VERSION 5.7 ;
  NOWIREEXTENSIONATPIN ON ;
  DIVIDERCHAR "/" ;
  BUSBITCHARS "[]" ;
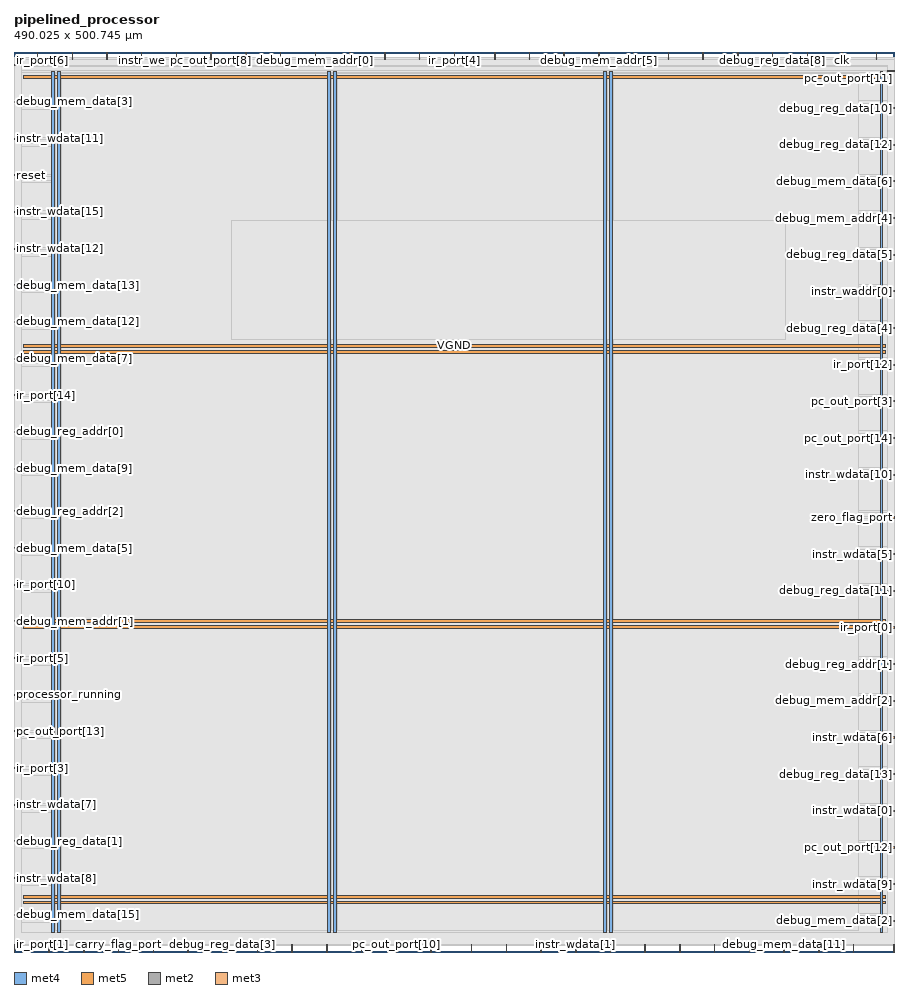
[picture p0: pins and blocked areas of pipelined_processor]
MACRO pipelined_processor
  CLASS BLOCK ;
  FOREIGN pipelined_processor ;
  ORIGIN 0.000 0.000 ;
  SIZE 490.025 BY 500.745 ;
  PIN VGND
    DIRECTION INOUT ;
    USE GROUND ;
    PORT
      LAYER met4 ;
        RECT 24.340 10.640 25.940 489.840 ;
    END
    PORT
      LAYER met4 ;
        RECT 177.940 10.640 179.540 489.840 ;
    END
    PORT
      LAYER met4 ;
        RECT 331.540 10.640 333.140 489.840 ;
    END
    PORT
      LAYER met5 ;
        RECT 5.280 30.030 484.620 31.630 ;
    END
    PORT
      LAYER met5 ;
        RECT 5.280 183.210 484.620 184.810 ;
    END
    PORT
      LAYER met5 ;
        RECT 5.280 336.390 484.620 337.990 ;
    END
  END VGND
  PIN VPWR
    DIRECTION INOUT ;
    USE POWER ;
    PORT
      LAYER met4 ;
        RECT 21.040 10.640 22.640 489.840 ;
    END
    PORT
      LAYER met4 ;
        RECT 174.640 10.640 176.240 489.840 ;
    END
    PORT
      LAYER met4 ;
        RECT 328.240 10.640 329.840 489.840 ;
    END
    PORT
      LAYER met4 ;
        RECT 481.840 10.640 483.440 489.840 ;
    END
    PORT
      LAYER met5 ;
        RECT 5.280 26.730 484.620 28.330 ;
    END
    PORT
      LAYER met5 ;
        RECT 5.280 179.910 484.620 181.510 ;
    END
    PORT
      LAYER met5 ;
        RECT 5.280 333.090 484.620 334.690 ;
    END
    PORT
      LAYER met5 ;
        RECT 5.280 486.270 484.620 487.870 ;
    END
  END VPWR
  PIN carry_flag_port
    DIRECTION OUTPUT TRISTATE ;
    USE SIGNAL ;
    ANTENNADIFFAREA 0.795200 ;
    PORT
      LAYER met2 ;
        RECT 58.050 0.000 58.330 4.000 ;
    END
  END carry_flag_port
  PIN clk
    DIRECTION INPUT ;
    USE SIGNAL ;
    ANTENNAGATEAREA 1.286700 ;
    ANTENNADIFFAREA 0.434700 ;
    PORT
      LAYER met2 ;
        RECT 460.550 496.745 460.830 500.745 ;
    END
  END clk
  PIN debug_mem_addr[0]
    DIRECTION INPUT ;
    USE SIGNAL ;
    ANTENNAGATEAREA 0.213000 ;
    PORT
      LAYER met2 ;
        RECT 167.530 496.745 167.810 500.745 ;
    END
  END debug_mem_addr[0]
  PIN debug_mem_addr[1]
    DIRECTION INPUT ;
    USE SIGNAL ;
    ANTENNAGATEAREA 0.247500 ;
    PORT
      LAYER met3 ;
        RECT 0.000 183.640 4.000 184.240 ;
    END
  END debug_mem_addr[1]
  PIN debug_mem_addr[2]
    DIRECTION INPUT ;
    USE SIGNAL ;
    ANTENNAGATEAREA 0.159000 ;
    PORT
      LAYER met3 ;
        RECT 486.025 139.440 490.025 140.040 ;
    END
  END debug_mem_addr[2]
  PIN debug_mem_addr[3]
    DIRECTION INPUT ;
    USE SIGNAL ;
    ANTENNAGATEAREA 0.213000 ;
    PORT
      LAYER met2 ;
        RECT 363.950 496.745 364.230 500.745 ;
    END
  END debug_mem_addr[3]
  PIN debug_mem_addr[4]
    DIRECTION INPUT ;
    USE SIGNAL ;
    ANTENNAGATEAREA 0.247500 ;
    PORT
      LAYER met3 ;
        RECT 486.025 408.040 490.025 408.640 ;
    END
  END debug_mem_addr[4]
  PIN debug_mem_addr[5]
    DIRECTION INPUT ;
    USE SIGNAL ;
    ANTENNAGATEAREA 0.159000 ;
    PORT
      LAYER met2 ;
        RECT 325.310 496.745 325.590 500.745 ;
    END
  END debug_mem_addr[5]
  PIN debug_mem_data[0]
    DIRECTION OUTPUT TRISTATE ;
    USE SIGNAL ;
    ANTENNADIFFAREA 0.795200 ;
    PORT
      LAYER met2 ;
        RECT 409.030 0.000 409.310 4.000 ;
    END
  END debug_mem_data[0]
  PIN debug_mem_data[10]
    DIRECTION OUTPUT TRISTATE ;
    USE SIGNAL ;
    ANTENNADIFFAREA 0.795200 ;
    PORT
      LAYER met2 ;
        RECT 186.850 496.745 187.130 500.745 ;
    END
  END debug_mem_data[10]
  PIN debug_mem_data[11]
    DIRECTION OUTPUT TRISTATE ;
    USE SIGNAL ;
    ANTENNADIFFAREA 0.795200 ;
    PORT
      LAYER met2 ;
        RECT 428.350 0.000 428.630 4.000 ;
    END
  END debug_mem_data[11]
  PIN debug_mem_data[12]
    DIRECTION OUTPUT TRISTATE ;
    USE SIGNAL ;
    ANTENNADIFFAREA 0.795200 ;
    PORT
      LAYER met3 ;
        RECT 0.000 350.240 4.000 350.840 ;
    END
  END debug_mem_data[12]
  PIN debug_mem_data[13]
    DIRECTION OUTPUT TRISTATE ;
    USE SIGNAL ;
    ANTENNADIFFAREA 0.795200 ;
    PORT
      LAYER met3 ;
        RECT 0.000 370.640 4.000 371.240 ;
    END
  END debug_mem_data[13]
  PIN debug_mem_data[14]
    DIRECTION OUTPUT TRISTATE ;
    USE SIGNAL ;
    ANTENNADIFFAREA 0.795200 ;
    PORT
      LAYER met2 ;
        RECT 351.070 0.000 351.350 4.000 ;
    END
  END debug_mem_data[14]
  PIN debug_mem_data[15]
    DIRECTION OUTPUT TRISTATE ;
    USE SIGNAL ;
    ANTENNADIFFAREA 0.795200 ;
    PORT
      LAYER met3 ;
        RECT 0.000 20.440 4.000 21.040 ;
    END
  END debug_mem_data[15]
  PIN debug_mem_data[1]
    DIRECTION OUTPUT TRISTATE ;
    USE SIGNAL ;
    ANTENNADIFFAREA 0.795200 ;
    PORT
      LAYER met2 ;
        RECT 148.210 496.745 148.490 500.745 ;
    END
  END debug_mem_data[1]
  PIN debug_mem_data[2]
    DIRECTION OUTPUT TRISTATE ;
    USE SIGNAL ;
    ANTENNADIFFAREA 0.445500 ;
    PORT
      LAYER met3 ;
        RECT 486.025 17.040 490.025 17.640 ;
    END
  END debug_mem_data[2]
  PIN debug_mem_data[3]
    DIRECTION OUTPUT TRISTATE ;
    USE SIGNAL ;
    ANTENNADIFFAREA 0.795200 ;
    PORT
      LAYER met3 ;
        RECT 0.000 472.640 4.000 473.240 ;
    END
  END debug_mem_data[3]
  PIN debug_mem_data[4]
    DIRECTION OUTPUT TRISTATE ;
    USE SIGNAL ;
    ANTENNADIFFAREA 0.795200 ;
    PORT
      LAYER met2 ;
        RECT 466.990 0.000 467.270 4.000 ;
    END
  END debug_mem_data[4]
  PIN debug_mem_data[5]
    DIRECTION OUTPUT TRISTATE ;
    USE SIGNAL ;
    ANTENNADIFFAREA 0.795200 ;
    PORT
      LAYER met3 ;
        RECT 0.000 224.440 4.000 225.040 ;
    END
  END debug_mem_data[5]
  PIN debug_mem_data[6]
    DIRECTION OUTPUT TRISTATE ;
    USE SIGNAL ;
    ANTENNADIFFAREA 0.795200 ;
    PORT
      LAYER met3 ;
        RECT 486.025 428.440 490.025 429.040 ;
    END
  END debug_mem_data[6]
  PIN debug_mem_data[7]
    DIRECTION OUTPUT TRISTATE ;
    USE SIGNAL ;
    ANTENNADIFFAREA 0.795200 ;
    PORT
      LAYER met3 ;
        RECT 0.000 329.840 4.000 330.440 ;
    END
  END debug_mem_data[7]
  PIN debug_mem_data[8]
    DIRECTION OUTPUT TRISTATE ;
    USE SIGNAL ;
    ANTENNADIFFAREA 0.795200 ;
    PORT
      LAYER met2 ;
        RECT 51.610 496.745 51.890 500.745 ;
    END
  END debug_mem_data[8]
  PIN debug_mem_data[9]
    DIRECTION OUTPUT TRISTATE ;
    USE SIGNAL ;
    ANTENNADIFFAREA 0.795200 ;
    PORT
      LAYER met3 ;
        RECT 0.000 268.640 4.000 269.240 ;
    END
  END debug_mem_data[9]
  PIN debug_reg_addr[0]
    DIRECTION INPUT ;
    USE SIGNAL ;
    ANTENNAGATEAREA 0.247500 ;
    PORT
      LAYER met3 ;
        RECT 0.000 289.040 4.000 289.640 ;
    END
  END debug_reg_addr[0]
  PIN debug_reg_addr[1]
    DIRECTION INPUT ;
    USE SIGNAL ;
    ANTENNAGATEAREA 0.213000 ;
    PORT
      LAYER met3 ;
        RECT 486.025 159.840 490.025 160.440 ;
    END
  END debug_reg_addr[1]
  PIN debug_reg_addr[2]
    DIRECTION INPUT ;
    USE SIGNAL ;
    ANTENNAGATEAREA 0.247500 ;
    PORT
      LAYER met3 ;
        RECT 0.000 244.840 4.000 245.440 ;
    END
  END debug_reg_addr[2]
  PIN debug_reg_data[0]
    DIRECTION OUTPUT TRISTATE ;
    USE SIGNAL ;
    ANTENNADIFFAREA 0.795200 ;
    PORT
      LAYER met2 ;
        RECT 193.290 0.000 193.570 4.000 ;
    END
  END debug_reg_data[0]
  PIN debug_reg_data[10]
    DIRECTION OUTPUT TRISTATE ;
    USE SIGNAL ;
    ANTENNADIFFAREA 0.795200 ;
    PORT
      LAYER met3 ;
        RECT 486.025 469.240 490.025 469.840 ;
    END
  END debug_reg_data[10]
  PIN debug_reg_data[11]
    DIRECTION OUTPUT TRISTATE ;
    USE SIGNAL ;
    ANTENNADIFFAREA 0.795200 ;
    PORT
      LAYER met3 ;
        RECT 486.025 200.640 490.025 201.240 ;
    END
  END debug_reg_data[11]
  PIN debug_reg_data[12]
    DIRECTION OUTPUT TRISTATE ;
    USE SIGNAL ;
    ANTENNADIFFAREA 0.795200 ;
    PORT
      LAYER met3 ;
        RECT 486.025 448.840 490.025 449.440 ;
    END
  END debug_reg_data[12]
  PIN debug_reg_data[13]
    DIRECTION OUTPUT TRISTATE ;
    USE SIGNAL ;
    ANTENNADIFFAREA 0.795200 ;
    PORT
      LAYER met3 ;
        RECT 486.025 98.640 490.025 99.240 ;
    END
  END debug_reg_data[13]
  PIN debug_reg_data[14]
    DIRECTION OUTPUT TRISTATE ;
    USE SIGNAL ;
    ANTENNADIFFAREA 0.795200 ;
    PORT
      LAYER met2 ;
        RECT 305.990 496.745 306.270 500.745 ;
    END
  END debug_reg_data[14]
  PIN debug_reg_data[15]
    DIRECTION OUTPUT TRISTATE ;
    USE SIGNAL ;
    ANTENNADIFFAREA 0.795200 ;
    PORT
      LAYER met2 ;
        RECT 225.490 496.745 225.770 500.745 ;
    END
  END debug_reg_data[15]
  PIN debug_reg_data[1]
    DIRECTION OUTPUT TRISTATE ;
    USE SIGNAL ;
    ANTENNADIFFAREA 0.795200 ;
    PORT
      LAYER met3 ;
        RECT 0.000 61.240 4.000 61.840 ;
    END
  END debug_reg_data[1]
  PIN debug_reg_data[2]
    DIRECTION OUTPUT TRISTATE ;
    USE SIGNAL ;
    ANTENNADIFFAREA 0.795200 ;
    PORT
      LAYER met3 ;
        RECT 0.000 493.040 4.000 493.640 ;
    END
  END debug_reg_data[2]
  PIN debug_reg_data[3]
    DIRECTION OUTPUT TRISTATE ;
    USE SIGNAL ;
    ANTENNADIFFAREA 0.795200 ;
    PORT
      LAYER met2 ;
        RECT 116.010 0.000 116.290 4.000 ;
    END
  END debug_reg_data[3]
  PIN debug_reg_data[4]
    DIRECTION OUTPUT TRISTATE ;
    USE SIGNAL ;
    ANTENNADIFFAREA 0.445500 ;
    PORT
      LAYER met3 ;
        RECT 486.025 346.840 490.025 347.440 ;
    END
  END debug_reg_data[4]
  PIN debug_reg_data[5]
    DIRECTION OUTPUT TRISTATE ;
    USE SIGNAL ;
    ANTENNADIFFAREA 0.795200 ;
    PORT
      LAYER met3 ;
        RECT 486.025 387.640 490.025 388.240 ;
    END
  END debug_reg_data[5]
  PIN debug_reg_data[6]
    DIRECTION OUTPUT TRISTATE ;
    USE SIGNAL ;
    ANTENNADIFFAREA 0.795200 ;
    PORT
      LAYER met2 ;
        RECT 206.170 496.745 206.450 500.745 ;
    END
  END debug_reg_data[6]
  PIN debug_reg_data[7]
    DIRECTION OUTPUT TRISTATE ;
    USE SIGNAL ;
    ANTENNADIFFAREA 0.795200 ;
    PORT
      LAYER met2 ;
        RECT 267.350 496.745 267.630 500.745 ;
    END
  END debug_reg_data[7]
  PIN debug_reg_data[8]
    DIRECTION OUTPUT TRISTATE ;
    USE SIGNAL ;
    ANTENNADIFFAREA 0.795200 ;
    PORT
      LAYER met2 ;
        RECT 421.910 496.745 422.190 500.745 ;
    END
  END debug_reg_data[8]
  PIN debug_reg_data[9]
    DIRECTION OUTPUT TRISTATE ;
    USE SIGNAL ;
    ANTENNADIFFAREA 0.795200 ;
    PORT
      LAYER met2 ;
        RECT 489.530 0.000 489.810 4.000 ;
    END
  END debug_reg_data[9]
  PIN instr_waddr[0]
    DIRECTION INPUT ;
    USE SIGNAL ;
    ANTENNAGATEAREA 0.426000 ;
    PORT
      LAYER met3 ;
        RECT 486.025 367.240 490.025 367.840 ;
    END
  END instr_waddr[0]
  PIN instr_waddr[1]
    DIRECTION INPUT ;
    USE SIGNAL ;
    ANTENNAGATEAREA 0.426000 ;
    PORT
      LAYER met2 ;
        RECT 479.870 496.745 480.150 500.745 ;
    END
  END instr_waddr[1]
  PIN instr_waddr[2]
    DIRECTION INPUT ;
    USE SIGNAL ;
    ANTENNAGATEAREA 0.426000 ;
    PORT
      LAYER met2 ;
        RECT 286.670 496.745 286.950 500.745 ;
    END
  END instr_waddr[2]
  PIN instr_waddr[3]
    DIRECTION INPUT ;
    USE SIGNAL ;
    ANTENNAGATEAREA 0.213000 ;
    PORT
      LAYER met2 ;
        RECT 173.970 0.000 174.250 4.000 ;
    END
  END instr_waddr[3]
  PIN instr_wdata[0]
    DIRECTION INPUT ;
    USE SIGNAL ;
    ANTENNAGATEAREA 0.213000 ;
    PORT
      LAYER met3 ;
        RECT 486.025 78.240 490.025 78.840 ;
    END
  END instr_wdata[0]
  PIN instr_wdata[10]
    DIRECTION INPUT ;
    USE SIGNAL ;
    ANTENNAGATEAREA 0.213000 ;
    PORT
      LAYER met3 ;
        RECT 486.025 265.240 490.025 265.840 ;
    END
  END instr_wdata[10]
  PIN instr_wdata[11]
    DIRECTION INPUT ;
    USE SIGNAL ;
    ANTENNAGATEAREA 0.213000 ;
    PORT
      LAYER met3 ;
        RECT 0.000 452.240 4.000 452.840 ;
    END
  END instr_wdata[11]
  PIN instr_wdata[12]
    DIRECTION INPUT ;
    USE SIGNAL ;
    ANTENNAGATEAREA 0.213000 ;
    PORT
      LAYER met3 ;
        RECT 0.000 391.040 4.000 391.640 ;
    END
  END instr_wdata[12]
  PIN instr_wdata[13]
    DIRECTION INPUT ;
    USE SIGNAL ;
    ANTENNAGATEAREA 0.159000 ;
    PORT
      LAYER met2 ;
        RECT 128.890 496.745 129.170 500.745 ;
    END
  END instr_wdata[13]
  PIN instr_wdata[14]
    DIRECTION INPUT ;
    USE SIGNAL ;
    ANTENNAGATEAREA 0.213000 ;
    PORT
      LAYER met2 ;
        RECT 370.390 0.000 370.670 4.000 ;
    END
  END instr_wdata[14]
  PIN instr_wdata[15]
    DIRECTION INPUT ;
    USE SIGNAL ;
    ANTENNAGATEAREA 0.213000 ;
    PORT
      LAYER met3 ;
        RECT 0.000 411.440 4.000 412.040 ;
    END
  END instr_wdata[15]
  PIN instr_wdata[1]
    DIRECTION INPUT ;
    USE SIGNAL ;
    ANTENNAGATEAREA 0.159000 ;
    PORT
      LAYER met2 ;
        RECT 312.430 0.000 312.710 4.000 ;
    END
  END instr_wdata[1]
  PIN instr_wdata[2]
    DIRECTION INPUT ;
    USE SIGNAL ;
    ANTENNAGATEAREA 0.196500 ;
    PORT
      LAYER met2 ;
        RECT 38.730 0.000 39.010 4.000 ;
    END
  END instr_wdata[2]
  PIN instr_wdata[3]
    DIRECTION INPUT ;
    USE SIGNAL ;
    ANTENNAGATEAREA 0.196500 ;
    PORT
      LAYER met2 ;
        RECT 135.330 0.000 135.610 4.000 ;
    END
  END instr_wdata[3]
  PIN instr_wdata[4]
    DIRECTION INPUT ;
    USE SIGNAL ;
    ANTENNAGATEAREA 0.213000 ;
    PORT
      LAYER met2 ;
        RECT 447.670 0.000 447.950 4.000 ;
    END
  END instr_wdata[4]
  PIN instr_wdata[5]
    DIRECTION INPUT ;
    USE SIGNAL ;
    ANTENNAGATEAREA 0.247500 ;
    PORT
      LAYER met3 ;
        RECT 486.025 221.040 490.025 221.640 ;
    END
  END instr_wdata[5]
  PIN instr_wdata[6]
    DIRECTION INPUT ;
    USE SIGNAL ;
    ANTENNAGATEAREA 0.213000 ;
    PORT
      LAYER met3 ;
        RECT 486.025 119.040 490.025 119.640 ;
    END
  END instr_wdata[6]
  PIN instr_wdata[7]
    DIRECTION INPUT ;
    USE SIGNAL ;
    ANTENNAGATEAREA 0.196500 ;
    PORT
      LAYER met3 ;
        RECT 0.000 81.640 4.000 82.240 ;
    END
  END instr_wdata[7]
  PIN instr_wdata[8]
    DIRECTION INPUT ;
    USE SIGNAL ;
    ANTENNAGATEAREA 0.196500 ;
    PORT
      LAYER met3 ;
        RECT 0.000 40.840 4.000 41.440 ;
    END
  END instr_wdata[8]
  PIN instr_wdata[9]
    DIRECTION INPUT ;
    USE SIGNAL ;
    ANTENNAGATEAREA 0.247500 ;
    PORT
      LAYER met3 ;
        RECT 486.025 37.440 490.025 38.040 ;
    END
  END instr_wdata[9]
  PIN instr_we
    DIRECTION INPUT ;
    USE SIGNAL ;
    ANTENNAGATEAREA 0.742500 ;
    PORT
      LAYER met2 ;
        RECT 70.930 496.745 71.210 500.745 ;
    END
  END instr_we
  PIN ir_port[0]
    DIRECTION OUTPUT TRISTATE ;
    USE SIGNAL ;
    ANTENNADIFFAREA 0.795200 ;
    PORT
      LAYER met3 ;
        RECT 486.025 180.240 490.025 180.840 ;
    END
  END ir_port[0]
  PIN ir_port[10]
    DIRECTION OUTPUT TRISTATE ;
    USE SIGNAL ;
    ANTENNADIFFAREA 0.795200 ;
    PORT
      LAYER met3 ;
        RECT 0.000 204.040 4.000 204.640 ;
    END
  END ir_port[10]
  PIN ir_port[11]
    DIRECTION OUTPUT TRISTATE ;
    USE SIGNAL ;
    ANTENNADIFFAREA 0.795200 ;
    PORT
      LAYER met2 ;
        RECT 389.710 0.000 389.990 4.000 ;
    END
  END ir_port[11]
  PIN ir_port[12]
    DIRECTION OUTPUT TRISTATE ;
    USE SIGNAL ;
    ANTENNADIFFAREA 0.795200 ;
    PORT
      LAYER met3 ;
        RECT 486.025 326.440 490.025 327.040 ;
    END
  END ir_port[12]
  PIN ir_port[13]
    DIRECTION OUTPUT TRISTATE ;
    USE SIGNAL ;
    ANTENNADIFFAREA 0.795200 ;
    PORT
      LAYER met2 ;
        RECT 90.250 496.745 90.530 500.745 ;
    END
  END ir_port[13]
  PIN ir_port[14]
    DIRECTION OUTPUT TRISTATE ;
    USE SIGNAL ;
    ANTENNADIFFAREA 0.795200 ;
    PORT
      LAYER met3 ;
        RECT 0.000 309.440 4.000 310.040 ;
    END
  END ir_port[14]
  PIN ir_port[15]
    DIRECTION OUTPUT TRISTATE ;
    USE SIGNAL ;
    ANTENNADIFFAREA 0.795200 ;
    PORT
      LAYER met2 ;
        RECT 231.930 0.000 232.210 4.000 ;
    END
  END ir_port[15]
  PIN ir_port[1]
    DIRECTION OUTPUT TRISTATE ;
    USE SIGNAL ;
    ANTENNADIFFAREA 0.795200 ;
    PORT
      LAYER met2 ;
        RECT 0.090 0.000 0.370 4.000 ;
    END
  END ir_port[1]
  PIN ir_port[2]
    DIRECTION OUTPUT TRISTATE ;
    USE SIGNAL ;
    ANTENNADIFFAREA 0.795200 ;
    PORT
      LAYER met2 ;
        RECT 293.110 0.000 293.390 4.000 ;
    END
  END ir_port[2]
  PIN ir_port[3]
    DIRECTION OUTPUT TRISTATE ;
    USE SIGNAL ;
    ANTENNADIFFAREA 0.795200 ;
    PORT
      LAYER met3 ;
        RECT 0.000 102.040 4.000 102.640 ;
    END
  END ir_port[3]
  PIN ir_port[4]
    DIRECTION OUTPUT TRISTATE ;
    USE SIGNAL ;
    ANTENNADIFFAREA 0.795200 ;
    PORT
      LAYER met2 ;
        RECT 244.810 496.745 245.090 500.745 ;
    END
  END ir_port[4]
  PIN ir_port[5]
    DIRECTION OUTPUT TRISTATE ;
    USE SIGNAL ;
    ANTENNADIFFAREA 0.795200 ;
    PORT
      LAYER met3 ;
        RECT 0.000 163.240 4.000 163.840 ;
    END
  END ir_port[5]
  PIN ir_port[6]
    DIRECTION OUTPUT TRISTATE ;
    USE SIGNAL ;
    ANTENNADIFFAREA 0.795200 ;
    PORT
      LAYER met2 ;
        RECT 12.970 496.745 13.250 500.745 ;
    END
  END ir_port[6]
  PIN ir_port[7]
    DIRECTION OUTPUT TRISTATE ;
    USE SIGNAL ;
    ANTENNADIFFAREA 0.795200 ;
    PORT
      LAYER met2 ;
        RECT 77.370 0.000 77.650 4.000 ;
    END
  END ir_port[7]
  PIN ir_port[8]
    DIRECTION OUTPUT TRISTATE ;
    USE SIGNAL ;
    ANTENNADIFFAREA 0.795200 ;
    PORT
      LAYER met2 ;
        RECT 19.410 0.000 19.690 4.000 ;
    END
  END ir_port[8]
  PIN ir_port[9]
    DIRECTION OUTPUT TRISTATE ;
    USE SIGNAL ;
    ANTENNADIFFAREA 0.795200 ;
    PORT
      LAYER met2 ;
        RECT 441.230 496.745 441.510 500.745 ;
    END
  END ir_port[9]
  PIN pc_out_port[0]
    DIRECTION OUTPUT TRISTATE ;
    USE SIGNAL ;
    ANTENNADIFFAREA 0.795200 ;
    PORT
      LAYER met2 ;
        RECT 344.630 496.745 344.910 500.745 ;
    END
  END pc_out_port[0]
  PIN pc_out_port[10]
    DIRECTION OUTPUT TRISTATE ;
    USE SIGNAL ;
    ANTENNADIFFAREA 0.795200 ;
    PORT
      LAYER met2 ;
        RECT 212.610 0.000 212.890 4.000 ;
    END
  END pc_out_port[10]
  PIN pc_out_port[11]
    DIRECTION OUTPUT TRISTATE ;
    USE SIGNAL ;
    ANTENNADIFFAREA 0.795200 ;
    PORT
      LAYER met3 ;
        RECT 486.025 489.640 490.025 490.240 ;
    END
  END pc_out_port[11]
  PIN pc_out_port[12]
    DIRECTION OUTPUT TRISTATE ;
    USE SIGNAL ;
    ANTENNADIFFAREA 0.795200 ;
    PORT
      LAYER met3 ;
        RECT 486.025 57.840 490.025 58.440 ;
    END
  END pc_out_port[12]
  PIN pc_out_port[13]
    DIRECTION OUTPUT TRISTATE ;
    USE SIGNAL ;
    ANTENNADIFFAREA 0.795200 ;
    PORT
      LAYER met3 ;
        RECT 0.000 122.440 4.000 123.040 ;
    END
  END pc_out_port[13]
  PIN pc_out_port[14]
    DIRECTION OUTPUT TRISTATE ;
    USE SIGNAL ;
    ANTENNADIFFAREA 0.795200 ;
    PORT
      LAYER met3 ;
        RECT 486.025 285.640 490.025 286.240 ;
    END
  END pc_out_port[14]
  PIN pc_out_port[15]
    DIRECTION OUTPUT TRISTATE ;
    USE SIGNAL ;
    ANTENNADIFFAREA 0.795200 ;
    PORT
      LAYER met2 ;
        RECT 96.690 0.000 96.970 4.000 ;
    END
  END pc_out_port[15]
  PIN pc_out_port[1]
    DIRECTION OUTPUT TRISTATE ;
    USE SIGNAL ;
    ANTENNADIFFAREA 0.795200 ;
    PORT
      LAYER met2 ;
        RECT 154.650 0.000 154.930 4.000 ;
    END
  END pc_out_port[1]
  PIN pc_out_port[2]
    DIRECTION OUTPUT TRISTATE ;
    USE SIGNAL ;
    ANTENNADIFFAREA 0.795200 ;
    PORT
      LAYER met2 ;
        RECT 254.470 0.000 254.750 4.000 ;
    END
  END pc_out_port[2]
  PIN pc_out_port[3]
    DIRECTION OUTPUT TRISTATE ;
    USE SIGNAL ;
    ANTENNADIFFAREA 0.795200 ;
    PORT
      LAYER met3 ;
        RECT 486.025 306.040 490.025 306.640 ;
    END
  END pc_out_port[3]
  PIN pc_out_port[4]
    DIRECTION OUTPUT TRISTATE ;
    USE SIGNAL ;
    ANTENNADIFFAREA 0.795200 ;
    PORT
      LAYER met2 ;
        RECT 273.790 0.000 274.070 4.000 ;
    END
  END pc_out_port[4]
  PIN pc_out_port[5]
    DIRECTION OUTPUT TRISTATE ;
    USE SIGNAL ;
    ANTENNADIFFAREA 0.795200 ;
    PORT
      LAYER met2 ;
        RECT 402.590 496.745 402.870 500.745 ;
    END
  END pc_out_port[5]
  PIN pc_out_port[6]
    DIRECTION OUTPUT TRISTATE ;
    USE SIGNAL ;
    ANTENNADIFFAREA 0.795200 ;
    PORT
      LAYER met2 ;
        RECT 383.270 496.745 383.550 500.745 ;
    END
  END pc_out_port[6]
  PIN pc_out_port[7]
    DIRECTION OUTPUT TRISTATE ;
    USE SIGNAL ;
    ANTENNADIFFAREA 0.795200 ;
    PORT
      LAYER met2 ;
        RECT 32.290 496.745 32.570 500.745 ;
    END
  END pc_out_port[7]
  PIN pc_out_port[8]
    DIRECTION OUTPUT TRISTATE ;
    USE SIGNAL ;
    ANTENNADIFFAREA 0.795200 ;
    PORT
      LAYER met2 ;
        RECT 109.570 496.745 109.850 500.745 ;
    END
  END pc_out_port[8]
  PIN pc_out_port[9]
    DIRECTION OUTPUT TRISTATE ;
    USE SIGNAL ;
    ANTENNADIFFAREA 0.795200 ;
    PORT
      LAYER met2 ;
        RECT 331.750 0.000 332.030 4.000 ;
    END
  END pc_out_port[9]
  PIN processor_running
    DIRECTION OUTPUT TRISTATE ;
    USE SIGNAL ;
    ANTENNADIFFAREA 0.795200 ;
    PORT
      LAYER met3 ;
        RECT 0.000 142.840 4.000 143.440 ;
    END
  END processor_running
  PIN reset
    DIRECTION INPUT ;
    USE SIGNAL ;
    ANTENNAGATEAREA 0.495000 ;
    PORT
      LAYER met3 ;
        RECT 0.000 431.840 4.000 432.440 ;
    END
  END reset
  PIN zero_flag_port
    DIRECTION OUTPUT TRISTATE ;
    USE SIGNAL ;
    ANTENNADIFFAREA 0.795200 ;
    PORT
      LAYER met3 ;
        RECT 486.025 241.440 490.025 242.040 ;
    END
  END zero_flag_port
  OBS
      LAYER li1 ;
        RECT 5.520 10.795 484.380 489.685 ;
      LAYER met1 ;
        RECT 0.070 8.540 488.450 489.840 ;
      LAYER met2 ;
        RECT 0.100 496.465 12.690 497.490 ;
        RECT 13.530 496.465 32.010 497.490 ;
        RECT 32.850 496.465 51.330 497.490 ;
        RECT 52.170 496.465 70.650 497.490 ;
        RECT 71.490 496.465 89.970 497.490 ;
        RECT 90.810 496.465 109.290 497.490 ;
        RECT 110.130 496.465 128.610 497.490 ;
        RECT 129.450 496.465 147.930 497.490 ;
        RECT 148.770 496.465 167.250 497.490 ;
        RECT 168.090 496.465 186.570 497.490 ;
        RECT 187.410 496.465 205.890 497.490 ;
        RECT 206.730 496.465 225.210 497.490 ;
        RECT 226.050 496.465 244.530 497.490 ;
        RECT 245.370 496.465 267.070 497.490 ;
        RECT 267.910 496.465 286.390 497.490 ;
        RECT 287.230 496.465 305.710 497.490 ;
        RECT 306.550 496.465 325.030 497.490 ;
        RECT 325.870 496.465 344.350 497.490 ;
        RECT 345.190 496.465 363.670 497.490 ;
        RECT 364.510 496.465 382.990 497.490 ;
        RECT 383.830 496.465 402.310 497.490 ;
        RECT 403.150 496.465 421.630 497.490 ;
        RECT 422.470 496.465 440.950 497.490 ;
        RECT 441.790 496.465 460.270 497.490 ;
        RECT 461.110 496.465 479.590 497.490 ;
        RECT 480.430 496.465 489.740 497.490 ;
        RECT 0.100 4.280 489.740 496.465 ;
        RECT 0.650 3.670 19.130 4.280 ;
        RECT 19.970 3.670 38.450 4.280 ;
        RECT 39.290 3.670 57.770 4.280 ;
        RECT 58.610 3.670 77.090 4.280 ;
        RECT 77.930 3.670 96.410 4.280 ;
        RECT 97.250 3.670 115.730 4.280 ;
        RECT 116.570 3.670 135.050 4.280 ;
        RECT 135.890 3.670 154.370 4.280 ;
        RECT 155.210 3.670 173.690 4.280 ;
        RECT 174.530 3.670 193.010 4.280 ;
        RECT 193.850 3.670 212.330 4.280 ;
        RECT 213.170 3.670 231.650 4.280 ;
        RECT 232.490 3.670 254.190 4.280 ;
        RECT 255.030 3.670 273.510 4.280 ;
        RECT 274.350 3.670 292.830 4.280 ;
        RECT 293.670 3.670 312.150 4.280 ;
        RECT 312.990 3.670 331.470 4.280 ;
        RECT 332.310 3.670 350.790 4.280 ;
        RECT 351.630 3.670 370.110 4.280 ;
        RECT 370.950 3.670 389.430 4.280 ;
        RECT 390.270 3.670 408.750 4.280 ;
        RECT 409.590 3.670 428.070 4.280 ;
        RECT 428.910 3.670 447.390 4.280 ;
        RECT 448.230 3.670 466.710 4.280 ;
        RECT 467.550 3.670 489.250 4.280 ;
      LAYER met3 ;
        RECT 4.400 492.640 486.025 493.490 ;
        RECT 3.990 490.640 486.025 492.640 ;
        RECT 3.990 489.240 485.625 490.640 ;
        RECT 3.990 473.640 486.025 489.240 ;
        RECT 4.400 472.240 486.025 473.640 ;
        RECT 3.990 470.240 486.025 472.240 ;
        RECT 3.990 468.840 485.625 470.240 ;
        RECT 3.990 453.240 486.025 468.840 ;
        RECT 4.400 451.840 486.025 453.240 ;
        RECT 3.990 449.840 486.025 451.840 ;
        RECT 3.990 448.440 485.625 449.840 ;
        RECT 3.990 432.840 486.025 448.440 ;
        RECT 4.400 431.440 486.025 432.840 ;
        RECT 3.990 429.440 486.025 431.440 ;
        RECT 3.990 428.040 485.625 429.440 ;
        RECT 3.990 412.440 486.025 428.040 ;
        RECT 4.400 411.040 486.025 412.440 ;
        RECT 3.990 409.040 486.025 411.040 ;
        RECT 3.990 407.640 485.625 409.040 ;
        RECT 3.990 392.040 486.025 407.640 ;
        RECT 4.400 390.640 486.025 392.040 ;
        RECT 3.990 388.640 486.025 390.640 ;
        RECT 3.990 387.240 485.625 388.640 ;
        RECT 3.990 371.640 486.025 387.240 ;
        RECT 4.400 370.240 486.025 371.640 ;
        RECT 3.990 368.240 486.025 370.240 ;
        RECT 3.990 366.840 485.625 368.240 ;
        RECT 3.990 351.240 486.025 366.840 ;
        RECT 4.400 349.840 486.025 351.240 ;
        RECT 3.990 347.840 486.025 349.840 ;
        RECT 3.990 346.440 485.625 347.840 ;
        RECT 3.990 330.840 486.025 346.440 ;
        RECT 4.400 329.440 486.025 330.840 ;
        RECT 3.990 327.440 486.025 329.440 ;
        RECT 3.990 326.040 485.625 327.440 ;
        RECT 3.990 310.440 486.025 326.040 ;
        RECT 4.400 309.040 486.025 310.440 ;
        RECT 3.990 307.040 486.025 309.040 ;
        RECT 3.990 305.640 485.625 307.040 ;
        RECT 3.990 290.040 486.025 305.640 ;
        RECT 4.400 288.640 486.025 290.040 ;
        RECT 3.990 286.640 486.025 288.640 ;
        RECT 3.990 285.240 485.625 286.640 ;
        RECT 3.990 269.640 486.025 285.240 ;
        RECT 4.400 268.240 486.025 269.640 ;
        RECT 3.990 266.240 486.025 268.240 ;
        RECT 3.990 264.840 485.625 266.240 ;
        RECT 3.990 245.840 486.025 264.840 ;
        RECT 4.400 244.440 486.025 245.840 ;
        RECT 3.990 242.440 486.025 244.440 ;
        RECT 3.990 241.040 485.625 242.440 ;
        RECT 3.990 225.440 486.025 241.040 ;
        RECT 4.400 224.040 486.025 225.440 ;
        RECT 3.990 222.040 486.025 224.040 ;
        RECT 3.990 220.640 485.625 222.040 ;
        RECT 3.990 205.040 486.025 220.640 ;
        RECT 4.400 203.640 486.025 205.040 ;
        RECT 3.990 201.640 486.025 203.640 ;
        RECT 3.990 200.240 485.625 201.640 ;
        RECT 3.990 184.640 486.025 200.240 ;
        RECT 4.400 183.240 486.025 184.640 ;
        RECT 3.990 181.240 486.025 183.240 ;
        RECT 3.990 179.840 485.625 181.240 ;
        RECT 3.990 164.240 486.025 179.840 ;
        RECT 4.400 162.840 486.025 164.240 ;
        RECT 3.990 160.840 486.025 162.840 ;
        RECT 3.990 159.440 485.625 160.840 ;
        RECT 3.990 143.840 486.025 159.440 ;
        RECT 4.400 142.440 486.025 143.840 ;
        RECT 3.990 140.440 486.025 142.440 ;
        RECT 3.990 139.040 485.625 140.440 ;
        RECT 3.990 123.440 486.025 139.040 ;
        RECT 4.400 122.040 486.025 123.440 ;
        RECT 3.990 120.040 486.025 122.040 ;
        RECT 3.990 118.640 485.625 120.040 ;
        RECT 3.990 103.040 486.025 118.640 ;
        RECT 4.400 101.640 486.025 103.040 ;
        RECT 3.990 99.640 486.025 101.640 ;
        RECT 3.990 98.240 485.625 99.640 ;
        RECT 3.990 82.640 486.025 98.240 ;
        RECT 4.400 81.240 486.025 82.640 ;
        RECT 3.990 79.240 486.025 81.240 ;
        RECT 3.990 77.840 485.625 79.240 ;
        RECT 3.990 62.240 486.025 77.840 ;
        RECT 4.400 60.840 486.025 62.240 ;
        RECT 3.990 58.840 486.025 60.840 ;
        RECT 3.990 57.440 485.625 58.840 ;
        RECT 3.990 41.840 486.025 57.440 ;
        RECT 4.400 40.440 486.025 41.840 ;
        RECT 3.990 38.440 486.025 40.440 ;
        RECT 3.990 37.040 485.625 38.440 ;
        RECT 3.990 21.440 486.025 37.040 ;
        RECT 4.400 20.040 486.025 21.440 ;
        RECT 3.990 18.040 486.025 20.040 ;
        RECT 3.990 16.640 485.625 18.040 ;
        RECT 3.990 10.715 486.025 16.640 ;
      LAYER met4 ;
        RECT 23.295 11.735 23.940 488.745 ;
        RECT 26.340 11.735 174.240 488.745 ;
        RECT 176.640 11.735 177.540 488.745 ;
        RECT 179.940 11.735 327.840 488.745 ;
        RECT 330.240 11.735 331.140 488.745 ;
        RECT 333.540 11.735 469.825 488.745 ;
      LAYER met5 ;
        RECT 121.100 340.900 429.060 407.100 ;
  END
END pipelined_processor
END LIBRARY

